VERSION 5.7 ;
BUSBITCHARS "[]" ;
DIVIDERCHAR "/" ;
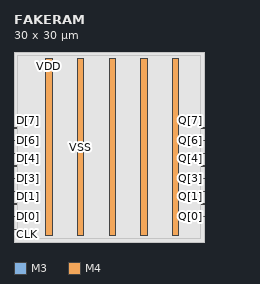
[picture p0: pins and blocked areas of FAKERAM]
MACRO FAKERAM
  CLASS BLOCK ;
  ORIGIN 0 0 ;
  FOREIGN FAKERAM 0 0 ;
  SIZE 30 BY 30 ;
  SYMMETRY X Y ;
  PIN CLK
    DIRECTION INPUT ;
    USE CLOCK ;
    PORT
      LAYER M3 ;
        RECT 0.000 1.950 0.400 2.050 ;
    END
  END CLK
  PIN D[0]
    DIRECTION INPUT ;
    USE SIGNAL ;
    PORT
      LAYER M3 ;
        RECT 0.000 3.950 0.400 4.050 ;
    END
  END D[0]
  PIN Q[0]
    DIRECTION OUTPUT ;
    USE SIGNAL ;
    PORT
      LAYER M3 ;
        RECT 29.600 3.950 30.000 4.050 ;
    END
  END Q[0]
  PIN D[1]
    DIRECTION INPUT ;
    USE SIGNAL ;
    PORT
      LAYER M3 ;
        RECT 0.000 5.950 0.400 6.050 ;
    END
  END D[1]
  PIN Q[1]
    DIRECTION OUTPUT ;
    USE SIGNAL ;
    PORT
      LAYER M3 ;
        RECT 29.600 5.950 30.000 6.050 ;
    END
  END Q[1]
  PIN D[2]
    DIRECTION INPUT ;
    USE SIGNAL ;
    PORT
      LAYER M3 ;
        RECT 0.000 7.950 0.400 8.050 ;
    END
  END D[2]
  PIN Q[2]
    DIRECTION OUTPUT ;
    USE SIGNAL ;
    PORT
      LAYER M3 ;
        RECT 29.600 7.950 30.000 8.050 ;
    END
  END Q[2]
  PIN D[3]
    DIRECTION INPUT ;
    USE SIGNAL ;
    PORT
      LAYER M3 ;
        RECT 0.000 9.950 0.400 10.050 ;
    END
  END D[3]
  PIN Q[3]
    DIRECTION OUTPUT ;
    USE SIGNAL ;
    PORT
      LAYER M3 ;
        RECT 29.600 9.950 30.000 10.050 ;
    END
  END Q[3]
  PIN D[4]
    DIRECTION INPUT ;
    USE SIGNAL ;
    PORT
      LAYER M3 ;
        RECT 0.000 11.950 0.400 12.050 ;
    END
  END D[4]
  PIN Q[4]
    DIRECTION OUTPUT ;
    USE SIGNAL ;
    PORT
      LAYER M3 ;
        RECT 29.600 11.950 30.000 12.050 ;
    END
  END Q[4]
  PIN D[5]
    DIRECTION INPUT ;
    USE SIGNAL ;
    PORT
      LAYER M3 ;
        RECT 0.000 13.950 0.400 14.050 ;
    END
  END D[5]
  PIN Q[5]
    DIRECTION OUTPUT ;
    USE SIGNAL ;
    PORT
      LAYER M3 ;
        RECT 29.600 13.950 30.000 14.050 ;
    END
  END Q[5]
  PIN D[6]
    DIRECTION INPUT ;
    USE SIGNAL ;
    PORT
      LAYER M3 ;
        RECT 0.000 15.950 0.400 16.050 ;
    END
  END D[6]
  PIN Q[6]
    DIRECTION OUTPUT ;
    USE SIGNAL ;
    PORT
      LAYER M3 ;
        RECT 29.600 15.950 30.000 16.050 ;
    END
  END Q[6]
  PIN D[7]
    DIRECTION INPUT ;
    USE SIGNAL ;
    PORT
      LAYER M3 ;
        RECT 0.000 17.950 0.400 18.050 ;
    END
  END D[7]
  PIN Q[7]
    DIRECTION OUTPUT ;
    USE SIGNAL ;
    PORT
      LAYER M3 ;
        RECT 29.600 17.950 30.000 18.050 ;
    END
  END Q[7]
  PIN VDD
    DIRECTION INOUT ;
    USE POWER ;
    PORT
      LAYER M4 ;
        RECT 5.000 1.000 6.000 29.000 ;
        RECT 15.000 1.000 16.000 29.000 ;
        RECT 25.000 1.000 26.000 29.000 ;
    END
  END VDD
  PIN VSS
    DIRECTION INOUT ;
    USE GROUND ;
    PORT
      LAYER M4 ;
        RECT 10.000 1.000 11.000 29.000 ;
        RECT 20.000 1.000 21.000 29.000 ;
    END
  END VSS
  OBS
    LAYER M1 ;
      RECT 0 0 30 30 ;
    LAYER M2 ;
      RECT 0 0 30 30 ;
    LAYER M3 ;
      RECT 0.6 0.6 29.4 29.4 ;
  END
END FAKERAM
END LIBRARY
